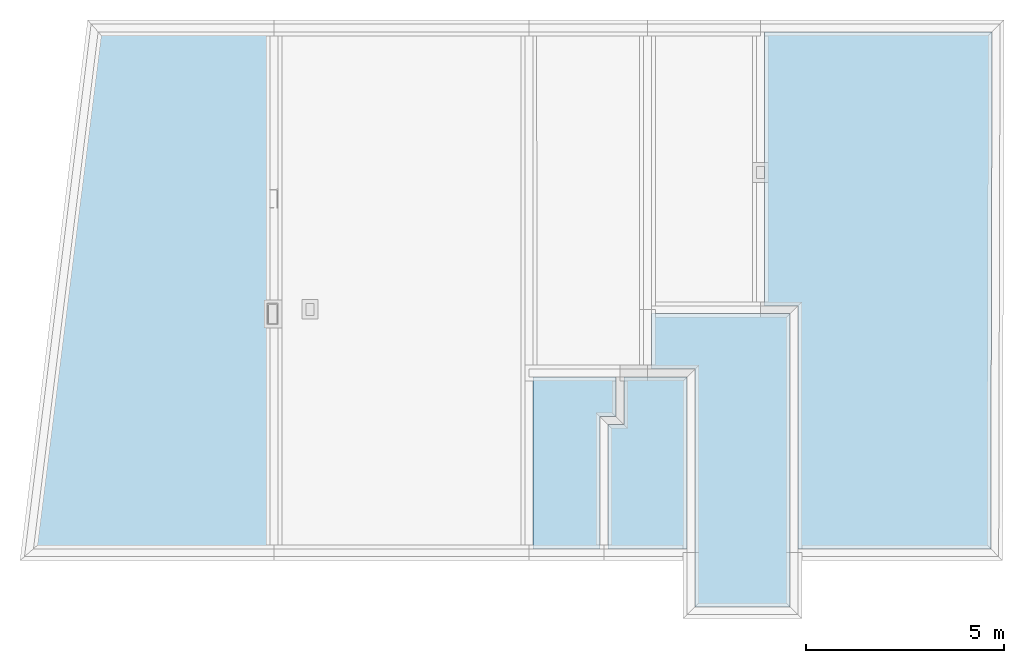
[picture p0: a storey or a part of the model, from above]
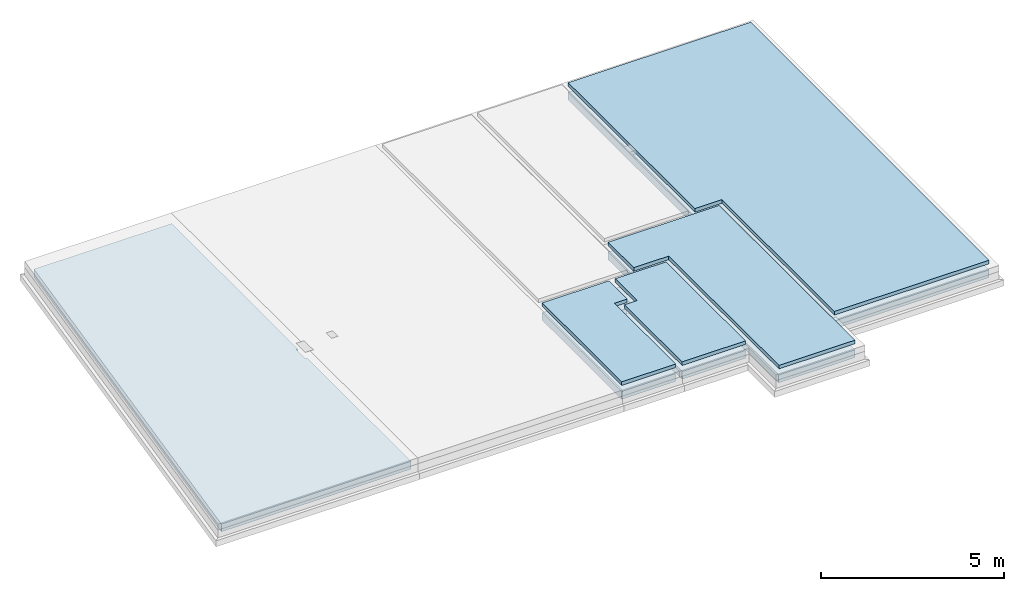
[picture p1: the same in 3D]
Properties of the parts of a building model (IFC2X3)

# File
Description: ISANGARD maison de santé et 9 logements, ViewDefinition [CoordinationView]
File name: G:\2024 Freyssinet\2024_Administratif\Administratif\Eduscol\2024 2025\ATTIC+ ISANGARD\Ressources\Divers\Projte ISANGARD_Ouvrages GO.IFC
Time: 2025-04-09T10:46:59
Author: Philippe PETIT
Organization: Lycée FREYSSINET
Written by: 2023-B
Made in: ATTIC+ Classic-Pack / Graphic-Pack Export_IFC 2023-B
Authorization: Personnes autorisées

# IfcProject, ISANGARD maison de santé et 9 logements
Description: ISANGARD maison de santé et 9 logements; Phase: EXE GROS OEUVRE ISANGARD

# IfcSite
RefLatitude: 0, 0, 0; RefLongitude: 0, 0, 0; RefElevation: 0 m

# IfcBuilding, Classeur ENS Ensemble
LongName: Classeur ENS Ensemble

# IfcBuildingStorey (5)
In: Classeur ENS Ensemble
Name | Description = LongName | Elevation (m)
000 Fondations | 000 Fondations | 0
001 RdC | 001 RdC | 0
002 R+1 | 002 R+1 | 3.3
003 R+2 | 003 R+2 | 6.03
004 Toiture Terrasse | 004 Toiture Terrasse | 8.73

# IfcBeam (184)
Type - PredefinedType: BEAM
Material: Default material
Name | In | Description | NominalLength (m) | CrossSectionArea (m2) | TotalSurfaceArea (m2) | OuterSurfaceArea (m2) | GrossVolume (m3)
3 x poutre fictive -32 | 000 Fondations | poutre fictive -32 | 0.15 | 0 | 0 | 0 | 0
7 x poutre fictive -32 | 000 Fondations | poutre fictive -32 | 0.1 | 0 | 0 | 0 | 0
poutre fictive -32 | 000 Fondations | poutre fictive -32 | 0.45 | 0 | 0 | 0 | 0
2 x poutre fictive -32 | 000 Fondations | poutre fictive -32 | 0.5 | 0 | 0 | 0 | 0
poutre fictive -32 | 000 Fondations | poutre fictive -32 | 0.0198567 | 0 | 0 | 0 | 0
poutre BA | 001 RdC | poutre BA | 4.87555 | 0.08 | 5.93066 | 1.95022 | 0.390044
poutre BA | 001 RdC | poutre BA | 0.0198567 | 0.175 | 0.212728 | 0.0138997 | 0.00347491
poutre BA | 001 RdC | poutre BA | 2.31 | 0.175 | 4.494 | 1.617 | 0.40425
poutre BA | 001 RdC | poutre BA | 1.31 | 0.175 | 2.5765 | 0.917 | 0.22925
poutre BA | 001 RdC | poutre BA | 1.60246 | 0.175 | 3.14951 | 1.12172 | 0.28043
poutre BA | 001 RdC | poutre BA | 1.07043 | 0.125 | 1.73064 | 0.535213 | 0.133803
poutre BA | 001 RdC | poutre BA | 3.215 | 0.07 | 3.6065 | 1.12525 | 0.22505
poutre BA | 001 RdC | poutre BA | 3.405 | 0.07 | 3.8155 | 1.19175 | 0.23835
poutre fictive | 001 RdC | poutre fictive | 0.075 | 0 | 0 | 0 | 0
poutre fictive | 001 RdC | poutre fictive | 0.125 | 0 | 0 | 0 | 0
poutre BA | 001 RdC | poutre BA | 1.23514 | 0.175 | 2.43427 | 0.8646 | 0.21615
poutre fictive | 001 RdC | poutre fictive | 0.63277 | 0 | 0 | 0 | 0
poutre fictive | 001 RdC | poutre fictive | 1.4652 | 0 | 0 | 0 | 0
poutre fictive | 001 RdC | poutre fictive | 5.06775 | 0 | 0 | 0 | 0
poutre fictive | 001 RdC | poutre fictive | 1.465 | 0 | 0 | 0 | 0
poutre fictive | 001 RdC | poutre fictive | 5.07148 | 0 | 0 | 0 | 0
poutre fictive | 001 RdC | poutre fictive | 0.1 | 0 | 0 | 0 | 0
poutre BA | 001 RdC | poutre BA | 0.1 | 0.04 | 0.12 | 0.02 | 0.004
poutre fictive | 001 RdC | poutre fictive | 0.124967 | 0 | 0 | 0 | 0
poutre fictive 285 | 001 RdC | poutre fictive 285 | 0.00999995 | 0 | 0 | 0 | 0
2 x poutre fictive 285 | 001 RdC | poutre fictive 285 | 0.12 | 0 | 0 | 0 | 0
Poutre auto | 001 RdC | Poutre auto | 5.88381 | 0 | 2.35352 | 1.17676 | 0
poutre BA | 001 RdC | poutre BA | 3.665 | 0.125 | 5.6225 | 1.8325 | 0.458125
poutre BA | 001 RdC | poutre BA | 0.120949 | 0.125 | 0.256424 | 0.0604747 | 0.0151187
poutre BA | 001 RdC | poutre BA | 1.56247 | 0.09 | 2.12121 | 0.70311 | 0.140622
poutre BA | 001 RdC | poutre BA | 0.1 | 0.09 | 0.22 | 0.045 | 0.009
poutre fictive 285 | 001 RdC | poutre fictive 285 | 0.1 | 0 | 0 | 0 | 0
poutre BA | 001 RdC | poutre BA | 0.1 | 0.125 | 0.225 | 0.05 | 0.0125
poutre BA | 001 RdC | poutre BA | 2.74002 | 0.09 | 3.65202 | 1.23301 | 0.246601
poutre BA | 001 RdC | poutre BA | 0.249984 | 0.09 | 0.190008 | 0.00000737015 | 0.00000147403
poutre BA | 001 RdC | poutre BA | 1.6 | 0.04 | 1.32 | 0.32 | 0.064
poutre fictive 310 | 001 RdC | poutre fictive 310 | 2.83619 | 0 | 0 | 0 | 0
poutre BA | 001 RdC | poutre BA | 1.2 | 0.04 | 1 | 0.24 | 0.048
poutre fictive 310 | 001 RdC | poutre fictive 310 | 4.34 | 0 | 0 | 0 | 0
Bande noyée 20 x 20 | 001 RdC | Bande noyée 20 x 20 | 1.113 | 0.04 | 0.930403 | 0.222601 | 0.0445201
poutre BA | 001 RdC | poutre BA | 3.93 | 0.175 | 7.572 | 2.751 | 0.68775
poutre BA | 001 RdC | poutre BA | 3.93001 | 0.175 | 7.57217 | 2.751 | 0.687751
poutre BA rive balcon | 001 RdC | poutre BA rive balcon | 1.40084 | 0.075 | 1.8961 | 0.700422 | 0.105063
poutre BA rive balcon | 001 RdC | poutre BA rive balcon | 0.0755851 | 0.075 | 0.182647 | 0.0377926 | 0.00566888
poutre BA rive balcon | 001 RdC | poutre BA rive balcon | 2.63125 | 0.075 | 3.49563 | 1.31563 | 0.197344
poutre BA rive balcon | 001 RdC | poutre BA rive balcon | 4.46986 | 0.075 | 5.88582 | 2.23493 | 0.335239
poutre fictive 290 | 001 RdC | poutre fictive 290 | 1.415 | 0 | 0 | 0 | 0
poutre fictive 290 | 001 RdC | poutre fictive 290 | 0.075 | 0 | 0 | 0 | 0
poutre fictive 290 | 001 RdC | poutre fictive 290 | 1.49 | 0 | 0 | 0 | 0
2 x poutre fictive 306 | 001 RdC | poutre fictive 306 | 0.075 | 0 | 0 | 0 | 0
3 x poutre fictive 306 | 001 RdC | poutre fictive 306 | 0.0755851 | 0 | 0 | 0 | 0
poutre fictive 306 | 001 RdC | poutre fictive 306 | 0.1 | 0 | 0 | 0 | 0
poutre BA rive balcon | 001 RdC | poutre BA rive balcon | 2.36401 | 0.075 | 3.14821 | 1.182 | 0.177301
poutre fictive 306 | 001 RdC | poutre fictive 306 | 4.82129 | 0 | 0 | 0 | 0
poutre fictive 306 | 001 RdC | poutre fictive 306 | 4.98587 | 0 | 0 | 0 | 0
poutre fictive 306 | 001 RdC | poutre fictive 306 | 1.315 | 0 | 0 | 0 | 0
poutre fictive 306 | 001 RdC | poutre fictive 306 | 1.32526 | 0 | 0 | 0 | 0
4 x poutre fictive 305 | 001 RdC | poutre fictive 305 | 0.1 | 0 | 0 | 0 | 0
2 x poutre fictive 305 | 001 RdC | poutre fictive 305 | 1.265 | 0 | 0 | 0 | 0
2 x poutre fictive 305 | 001 RdC | poutre fictive 305 | 0.2 | 0 | 0 | 0 | 0
poutre fictive 305 | 001 RdC | poutre fictive 305 | 0.360863 | 0 | 0 | 0 | 0
2 x poutre fictive 305 | 001 RdC | poutre fictive 305 | 6.74 | 0 | 0 | 0 | 0
poutre BA 20 x 40 | 001 RdC | poutre BA 20 x 40 | 0.2 | 0.08 | 0.32 | 5.92039e-10 | 1.18408e-10
poutre BA 20 x 40 | 001 RdC | poutre BA 20 x 40 | 2.4 | 0.08 | 3.12 | 0.96 | 0.192
poutre fictive 290 | 001 RdC | poutre fictive 290 | 0.2 | 0 | 0 | 0 | 0
poutre BA rive balcon | 001 RdC | poutre BA rive balcon | 2.725 | 0.045 | 2.4975 | 0.8175 | 0.122625
poutre BA rive balcon | 001 RdC | poutre BA rive balcon | 1.49 | 0.045 | 1.386 | 0.447 | 0.06705
poutre voile BA 20 cm | 002 R+1 | poutre voile BA 20 cm | 0.0566479 | 0.596 | 0.956281 | 0.168811 | 0.0337622
poutre voile BA 20 cm | 002 R+1 | poutre voile BA 20 cm | 1.58 | 0.596 | 10.0488 | 4.7084 | 0.94168
poutre voile BA 20 cm | 002 R+1 | poutre voile BA 20 cm | 1.265 | 0.596 | 9.8334 | 3.7697 | 0.75394
poutre voile BA 20 cm | 002 R+1 | poutre voile BA 20 cm | 5.78 | 0.596 | 38.2508 | 17.2244 | 3.44488
2 x poutre voile BA 20 cm | 002 R+1 | poutre voile BA 20 cm | 1.265 | 0.586 | 8.5049 | 3.70645 | 0.74129
poutre fictive 250 | 002 R+1 | poutre fictive 250 | 2.96294 | 0 | 0 | 0 | 0
poutre voile BA 20 cm | 002 R+1 | poutre voile BA 20 cm | 1.56331 | 0.596 | 10.5386 | 4.65865 | 0.931731
poutre voile BA 20 cm | 002 R+1 | poutre voile BA 20 cm | 2.58416 | 0.596 | 16.6588 | 7.70079 | 1.54016
poutre BA 20 x 48 | 002 R+1 | poutre BA 20 x 48 | 2.75374 | 0.096 | 3.84108 | 1.32179 | 0.264359
poutre BA 20 x 35 | 002 R+1 | poutre BA 20 x 35 | 4.57052 | 0.07 | 5.09757 | 1.59968 | 0.319936
poutre BA 20 x 35 | 002 R+1 | poutre BA 20 x 35 | 7.09 | 0.07 | 7.869 | 2.4815 | 0.4963
poutre BA 20 x 35 | 002 R+1 | poutre BA 20 x 35 | 0.2 | 0.07 | 0.29 | 0.07 | 0.014
2 x poutre fictive 250 | 002 R+1 | poutre fictive 250 | 1.5 | 0 | 0 | 0 | 0
2 x poutre fictive 250 | 002 R+1 | poutre fictive 250 | 1.70004 | 0 | 0 | 0 | 0
poutre BA 20 x 35 | 002 R+1 | poutre BA 20 x 35 | 3.62678 | 0.07 | 4.05946 | 1.26937 | 0.253875
poutre fictive 250 | 002 R+1 | poutre fictive 250 | 5.44 | 0 | 0 | 0 | 0
poutre fictive 250 | 002 R+1 | poutre fictive 250 | 3.94 | 0 | 0 | 0 | 0
poutre fictive 250 | 002 R+1 | poutre fictive 250 | 1.6 | 0 | 0 | 0 | 0
poutre fictive 250 | 002 R+1 | poutre fictive 250 | 4.78032 | 0 | 0 | 0 | 0
poutre fictive 250 | 002 R+1 | poutre fictive 250 | 2.86496 | 0 | 0 | 0 | 0
poutre fictive 250 | 002 R+1 | poutre fictive 250 | 2.84982 | 0 | 0 | 0 | 0
poutre BA 25 x 45 | 002 R+1 | poutre BA 25 x 45 | 1.87996 | 0.1125 | 2.74444 | 0.84598 | 0.211495
poutre fictive 250 | 002 R+1 | poutre fictive 250 | 2.00327 | 0 | 0 | 0 | 0
poutre BA 25 x 45 | 002 R+1 | poutre BA 25 x 45 | 0.2 | 0.1125 | 0.3925 | 0.09 | 0.0225
poutre BA 25 x 45 | 002 R+1 | poutre BA 25 x 45 | 3.42999 | 0.1125 | 4.91449 | 1.5435 | 0.385874
poutre BA 25 x 50 | 002 R+1 | poutre BA 25 x 50 | 1.05309 | 0.125 | 1.70464 | 0.526545 | 0.131636
poutre fictive 250 | 002 R+1 | poutre fictive 250 | 2.05496 | 0 | 0 | 0 | 0
poutre BA 25 x 50 | 002 R+1 | poutre BA 25 x 50 | 3.92014 | 0.07 | 4.38216 | 1.37205 | 0.27441
BN 23 | 002 R+1 | BN 23 | 1.73706 | 0.046 | 1.53987 | 0.399525 | 0.0799049
poutre fictive 250 | 002 R+1 | poutre fictive 250 | 2.5404 | 0 | 0 | 0 | 0
poutre fictive 250 | 002 R+1 | poutre fictive 250 | 2.25496 | 0 | 0 | 0 | 0
2 x poutre fictive 250 | 002 R+1 | poutre fictive 250 | 0.324552 | 0 | 0 | 0 | 0
poutre fictive 250 | 002 R+1 | poutre fictive 250 | 0.239541 | 0 | 0 | 0 | 0
poutre BA 25 x 45 | 002 R+1 | poutre BA 25 x 45 | 1.21004 | 0.1125 | 1.80656 | 0.544519 | 0.13613
poutre fictive 250 | 002 R+1 | poutre fictive 250 | 2.20308 | 0 | 0 | 0 | 0
poutre fictive 250 | 002 R+1 | poutre fictive 250 | 2.61028 | 0 | 0 | 0 | 0
BN 23 | 002 R+1 | BN 23 | 1.24257 | 0.046 | 1.11461 | 0.285792 | 0.0571584
poutre BA 25 x 50 | 002 R+1 | poutre BA 25 x 50 | 0.199977 | 0.125 | 0.424965 | 0.0999883 | 0.0249971
poutre BA 25 x 50 | 002 R+1 | poutre BA 25 x 50 | 3.6341 | 0.125 | 5.57615 | 1.81705 | 0.454262
poutre voile BA 20 cm | 002 R+1 | poutre voile BA 20 cm | 0.260305 | 0.596 | 2.25154 | 0.77571 | 0.155142
Poutre auto | 002 R+1 | Poutre auto | 5.3 | 0 | 2.438 | 1.219 | 0
BN 23 | 002 R+1 | BN 23 | 1.55743 | 0.046 | 1.38539 | 0.358208 | 0.0716416
poutre fictive 250 | 002 R+1 | poutre fictive 250 | 1.50225 | 0 | 0 | 0 | 0
poutre voile BA 20 cm | 002 R+1 | poutre voile BA 20 cm | 0.0437805 | 0.596 | 0.874444 | 0.130466 | 0.0260932
BN 23 | 002 R+1 | BN 23 | 1.30238 | 0.046 | 1.16605 | 0.299547 | 0.0599095
poutre voile BA 20 cm | 002 R+1 | poutre voile BA 20 cm | 0.26 | 0.596 | 1.9516 | 0.7748 | 0.15496
poutre BA 25 x 50 | 002 R+1 | poutre BA 25 x 50 | 4.17955 | 0.125 | 6.39432 | 2.08977 | 0.522443
poutre voile BA 20 cm | 002 R+1 | poutre voile BA 20 cm | 2.11262 | 0.596 | 13.6598 | 6.29561 | 1.25912
poutre fictive 250 | 002 R+1 | poutre fictive 250 | 0.0750014 | 0 | 0 | 0 | 0
poutre BA 25 x 50 | 002 R+1 | poutre BA 25 x 50 | 3.74 | 0.125 | 5.735 | 1.87 | 0.4675
PV BA 20 cm | 003 R+2 | PV BA 20 cm | 5.01991 | 0.586 | 32.0107 | 14.7083 | 2.94167
PV BA 20 cm | 003 R+2 | PV BA 20 cm | 0.300186 | 0.586 | 2.46517 | 0.879546 | 0.175909
PV BA 20 cm | 003 R+2 | PV BA 20 cm | 0.2 | 0.586 | 0.666 | 4.36599e-09 | 8.73199e-10
2 x PV BA 20 cm | 003 R+2 | PV BA 20 cm | 0.14 | 0.586 | 1.4624 | 0.4102 | 0.08204
PV BA 20 cm | 003 R+2 | PV BA 20 cm | 4.95291 | 0.586 | 31.5912 | 14.512 | 2.9024
PV BA 20 cm | 003 R+2 | PV BA 20 cm | 0.1 | 0.586 | 1.212 | 0.293 | 0.0586
poutre BA 20 x 45 | 003 R+2 | poutre BA 20 x 45 | 4.84004 | 0.09 | 6.38206 | 2.17802 | 0.435604
poutre BA 20 x 35 | 003 R+2 | poutre BA 20 x 35 | 3.91107 | 0.07 | 4.37217 | 1.36887 | 0.273775
BN 20 | 003 R+2 | BN 20 | 0.0310394 | 0.04 | 0.117875 | 0.00620788 | 0.00124158
BN 20 | 003 R+2 | BN 20 | 1.70036 | 0.04 | 1.39418 | 0.340072 | 0.0680145
BN 20 | 003 R+2 | BN 20 | 1.28 | 0.04 | 1.064 | 0.256 | 0.0512
BN 20 | 003 R+2 | BN 20 | 1.22 | 0.04 | 1.016 | 0.244 | 0.0488
poutre BA 20 x 40 | 003 R+2 | poutre BA 20 x 40 | 4.44 | 0.08 | 5.408 | 1.776 | 0.3552
2 x poutre BA 20 x 30 | 003 R+2 | poutre BA 20 x 30 | 3.44 | 0.06 | 3.5 | 1.032 | 0.2064
PV BA 20 cm | 003 R+2 | PV BA 20 cm | 0.0114892 | 0.586 | 0.883596 | 0.0336634 | 0.00673267
2 x poutre BA 20 x 30 | 003 R+2 | poutre BA 20 x 30 | 0.1 | 0.06 | 0.13 | 0.03 | 0.006
poutre BA 20 x 50 | 003 R+2 | poutre BA 20 x 50 | 2.76138 | 0.1 | 3.96593 | 1.38069 | 0.276138
PV BA 20 cm | 003 R+2 | PV BA 20 cm | 0.0885108 | 0.586 | 0.914404 | 0.259337 | 0.0518673
PV BA 20 cm | 003 R+2 | PV BA 20 cm | 1.65004 | 0.586 | 10.9153 | 4.83462 | 0.966925
3 x Poutre auto | 003 R+2 | Poutre auto | 1.2 | 0 | 0.48 | 0.24 | 0
Poutre auto | 003 R+2 | Poutre auto | 0.151589 | 0 | 0.0606357 | 0.0303178 | 0
4 x poutre fictive 250 | 003 R+2 | poutre fictive 250 | 0.1 | 0 | 0 | 0 | 0
PV BA 20 cm | 003 R+2 | PV BA 20 cm | 2.725 | 0.64 | 19.17 | 8.72 | 1.744
PV BA 20 cm | 003 R+2 | PV BA 20 cm | 2.775 | 0.64 | 19.51 | 8.88 | 1.776
2 x poutre fictive 250 | 003 R+2 | poutre fictive 250 | 0.14 | 0 | 0 | 0 | 0
2 x poutre fictive 250 | 003 R+2 | poutre fictive 250 | 0.0114892 | 0 | 0 | 0 | 0
2 x poutre fictive 250 | 003 R+2 | poutre fictive 250 | 2.81351 | 0 | 0 | 0 | 0
2 x poutre fictive 250 | 003 R+2 | poutre fictive 250 | 6.88 | 0 | 0 | 0 | 0
PV BA 20 cm | 003 R+2 | PV BA 20 cm | 3.84 | 0.586 | 24.6244 | 11.2512 | 2.25024
PV BA 20 cm | 003 R+2 | PV BA 20 cm | 0.138512 | 0.586 | 1.00172 | 0.18016 | 0.036032
Poutre auto | 003 R+2 | Poutre auto | 1.04841 | 0 | 0.419364 | 0.209682 | 0
poutre BA 20 x 30 | 003 R+2 | poutre BA 20 x 30 | 0.2 | 0.06 | 0.14 | 4.4703e-10 | 8.9406e-11

# IfcColumn (8)
Type - PredefinedType: COLUMN
Description: Poteau BA; Material: Default material
Name | In | GrossVolume (m3) = NetVolume (m3) | TotalSurfaceArea (m2) | CrossSectionArea (m2) | NominalLength (m) | OuterSurfaceArea (m2)
Poteau BA | 001 RdC | 0.39625 | 5.005 | 0.125 | 3.17 | 4.755
Poteau BA | 001 RdC | 0.1902 | 3.29 | 0.06 | 3.17 | 3.17
Poteau BA | 001 RdC | 0.2853 | 4.301 | 0.09 | 3.17 | 4.121
Poteau BA | 001 RdC | 0.183 | 3.17 | 0.06 | 3.05 | 3.05
Poteau BA | 002 R+1 | 0.125 | 2.35 | 0.05 | 2.5 | 2.25
Poteau BA | 002 R+1 | 0.1 | 2.08 | 0.04 | 2.5 | 2
2 x Poteau BA | 003 R+2 | 0.1 | 2.08 | 0.04 | 2.5 | 2

# IfcDoor (18)
Description: Porte
Name | In | OverallHeight (m) | OverallWidth (m)
4 x BL 100 x 215 | 001 RdC | 2.15 | 1
PE 93 x 212 | 001 RdC | 2.15 | 1
2 x PS 103 x 210 | 001 RdC | 2.1 | 1.03
PE 95 x 215 | 001 RdC | 2.15 | 0.95
2 x BL 170 x 215 | 001 RdC | 2.15 | 1.7
4 x PE 93 x 215 | 002 R+1 | 2.15 | 1
4 x PE 93 x 215 | 003 R+2 | 2.15 | 1

# IfcFooting (34)
In: 000 Fondations
Description: Semelle filante 40x20; Material: Default material
Name | PredefinedType
31 x Semelle filante 40x20 | STRIP_FOOTING
3 x Semelle filante 40x20 | PAD_FOOTING

# IfcOpeningElement (66)
Name | In | Description | NominalArea (m2)
5 x BL 300 x 115 | 001 RdC | BL 300 x 115 | 3.45
BL 200 x 115 | 001 RdC | BL 200 x 115 | 2.3
4 x BL 100 x 215 | 001 RdC | BL 100 x 215 | 2.15
PE 93 x 212 | 001 RdC | PE 93 x 212 | 2.15
4 x BL 90 x 115 | 001 RdC | BL 90 x 115 | 1.035
BL 90 x 195 | 001 RdC | BL 90 x 195 | 1.755
BL 300 x 215 | 001 RdC | BL 300 x 215 | 6.45
2 x PS 103 x 210 | 001 RdC | PS 103 x 210 | 2.163
PE 95 x 215 | 001 RdC | PE 95 x 215 | 2.0425
2 x BL 170 x 215 | 001 RdC | BL 170 x 215 | 3.655
10 x BL 90 x 165 | 002 R+1 | BL 90 x 165 | 1.485
3 x BL 300 x 215 | 002 R+1 | BL 300 x 215 | 6.45
4 x PE 93 x 215 | 002 R+1 | PE 93 x 215 | 2.15
BL 80 x 165 | 002 R+1 | BL 80 x 165 | 1.32
BL 200 x 215 | 002 R+1 | BL 200 x 215 | 4.3
BL 90 x 115 | 002 R+1 | BL 90 x 115 | 1.035
BL 100 x 215 | 002 R+1 | BL 100 x 215 | 2.15
12 x BL 90 x 165 | 003 R+2 | BL 90 x 165 | 1.485
BL 300 x 215 | 003 R+2 | BL 300 x 215 | 6
2 x BL 200 x 200 | 003 R+2 | BL 200 x 200 | 4
BL 100 x 200 | 003 R+2 | BL 100 x 200 | 2
BL 80 x 165 | 003 R+2 | BL 80 x 165 | 1.32
BL 200 x 215 | 003 R+2 | BL 200 x 215 | 4.3
4 x PE 93 x 215 | 003 R+2 | PE 93 x 215 | 2.15
BL 90 x 115 | 003 R+2 | BL 90 x 115 | 1.035

# IfcSlab (73)
Description: description dalle à préciser; PredefinedType: FLOOR; Material: Default material
Pset_SlabCommon - LoadBearing: yes
Name | In | GrossVolume (m3) = NetVolume (m3) | Perimeter (m) | GrossArea (m2) = NetArea (m2) | NominalWidth (m)
dallage porté 20 cm | 000 Fondations | 1.9896 | 13.88 | 9.948 | 0.2
dallage porté 20 cm | 000 Fondations | 4.11542 | 20.1401 | 20.5771 | 0.2
dallage porté 20 cm | 000 Fondations | 15.1952 | 38.9973 | 75.976 | 0.2
dallage porté 20 cm | 000 Fondations | 4.49197 | 23.0099 | 22.4599 | 0.2
dallage porté 20 cm | 000 Fondations | 7.03557 | 32.9179 | 35.1779 | 0.2
dallage porté 20 cm | 000 Fondations | 17.3393 | 39.8021 | 86.6966 | 0.2
dallage porté 20 cm | 000 Fondations | 14.6988 | 37.9453 | 73.4938 | 0.2
chape sur isolant 12 cm | 000 Fondations | 2.86188 | 22.635 | 23.849 | 0.12
chape sur isolant 12 cm | 000 Fondations | 2.20056 | 19.14 | 18.338 | 0.12
chape sur isolant 12 cm | 000 Fondations | 8.3669 | 37.5968 | 69.7242 | 0.12
chape sur isolant 12 cm | 000 Fondations | 2.31383 | 21.7999 | 19.2819 | 0.12
chape sur isolant 12 cm | 000 Fondations | 0.93336 | 12.88 | 7.778 | 0.12
chape sur isolant 12 cm | 000 Fondations | 0.984 | 12.68 | 8.2 | 0.12
hérisson 26 cm | 000 Fondations | 17.51 | 36.6391 | 67.3463 | 0.26
hérisson 26 cm | 000 Fondations | 21.1921 | 38.6021 | 81.5081 | 0.26
hérisson 26 cm | 000 Fondations | 6.1786 | 22.615 | 23.7639 | 0.26
hérisson 26 cm | 000 Fondations | 4.76783 | 19.14 | 18.3378 | 0.26
hérisson 26 cm | 000 Fondations | 18.1283 | 37.5968 | 69.7242 | 0.26
hérisson 26 cm | 000 Fondations | 2.02228 | 12.88 | 7.778 | 0.26
hérisson 26 cm | 000 Fondations | 2.132 | 12.68 | 8.2 | 0.26
hérisson 26 cm | 000 Fondations | 5.02111 | 21.8099 | 19.3119 | 0.26
Dalle BA 20 cm | 001 RdC | 1.4855 | 13.0694 | 7.42749 | 0.2
Dalle BA 25 cm | 001 RdC | 3.7208 | 20.48 | 18.604 | 0.2
Dalle BA 25 cm | 001 RdC | 1.9016 | 13.48 | 9.508 | 0.2
Dalle BA 25 cm | 001 RdC | 15.1072 | 34.9826 | 60.4286 | 0.25
Dalle BA 25 cm | 001 RdC | 22.7054 | 51.7543 | 90.8216 | 0.25
Dalle BA 20 cm | 001 RdC | 0.811065 | 8.56147 | 4.05533 | 0.2
Dalle BA 20 cm | 001 RdC | 1.66055 | 23.4553 | 8.30274 | 0.2
Dalle BA 20 cm | 001 RdC | 17.2387 | 54.7424 | 86.1934 | 0.2
Dalle BA 20 cm | 001 RdC | 1.88282 | 14.9676 | 9.4141 | 0.2
Dalle BA 20 cm | 001 RdC | 1.58827 | 11.2724 | 7.94133 | 0.2
Dalle BA 20 cm | 001 RdC | 1.6396 | 13.28 | 8.198 | 0.2
Dalle BA 25 cm | 001 RdC | 1.37702 | 10.7935 | 5.50808 | 0.25
Dalle BA 20 cm | 001 RdC | 1.33148 | 12.169 | 6.65739 | 0.2
Dalle BA 20 cm | 001 RdC | 1.22516 | 12.4474 | 6.44821 | 0.19
Dalle BA 20 cm | 001 RdC | 1.70522 | 16.01 | 8.5261 | 0.2
isolant sous face 15 | 001 RdC | 1.27892 | 16.01 | 8.5261 | 0.15
Dalle BA 20 cm | 001 RdC | 0.8204 | 8.53 | 4.102 | 0.2
Dalle BA 18 cm | 002 R+1 | 0.630749 | 8.05916 | 3.50416 | 0.18
Dalle BA 23 cm | 002 R+1 | 1.13818 | 10.01 | 4.9486 | 0.23
Dalle BA 23 cm | 002 R+1 | 1.07999 | 9.61 | 4.6956 | 0.23
Dalle BA 18 cm | 002 R+1 | 2.09952 | 17.78 | 11.664 | 0.18
Dalle BA 18 cm | 002 R+1 | 1.23917 | 11.2491 | 6.88426 | 0.18
Dalle BA 18 cm | 002 R+1 | 1.40371 | 12.9581 | 7.79839 | 0.18
Dalle BA 23 cm | 002 R+1 | 1.23721 | 11.6362 | 5.37917 | 0.23
Dalle BA 23 cm | 002 R+1 | 2.52402 | 14.0399 | 10.974 | 0.23
Dalle BA 23 cm | 002 R+1 | 0.932159 | 8.11645 | 4.05287 | 0.23
Dalle BA 23 cm | 002 R+1 | 3.30361 | 15.7797 | 14.3635 | 0.23
Dalle BA 23 cm | 002 R+1 | 1.29778 | 9.65956 | 5.64253 | 0.23
Dalle BA 23 cm | 002 R+1 | 7.61935 | 23.66 | 33.1276 | 0.23
Dalle BA 23 cm | 002 R+1 | 9.00261 | 26.6831 | 39.1418 | 0.23
Dalle BA 23 cm | 002 R+1 | 2.67964 | 18.1 | 11.6506 | 0.23
Dalle BA 23 cm | 002 R+1 | 2.0204 | 13.9149 | 8.78436 | 0.23
Dalle BA 23 cm | 002 R+1 | 4.59393 | 18.96 | 19.9736 | 0.23
Dalle BA 23 cm | 002 R+1 | 8.0811 | 26.1539 | 35.1352 | 0.23
Dalle BA 23 cm | 002 R+1 | 8.4789 | 27.0246 | 36.8648 | 0.23
Dalle BA 23 cm | 002 R+1 | 4.70487 | 18.7817 | 20.456 | 0.23
Dalle BA 23 cm | 002 R+1 | 0.511386 | 5.96462 | 2.22342 | 0.23
Dalle BA 23 cm | 002 R+1 | 4.36871 | 17.7419 | 18.9944 | 0.23
Dalle BA 20 cm | 003 R+2 | 7.14872 | 26.4039 | 35.7436 | 0.2
Dalle BA 20 cm | 003 R+2 | 0.911289 | 9.00256 | 4.55645 | 0.2
Dalle BA 20 cm | 003 R+2 | 10.2801 | 40.9136 | 51.4003 | 0.2
Dalle BA 20 cm | 003 R+2 | 4.1476 | 26.2404 | 20.738 | 0.2
Dalle BA 20 cm | 003 R+2 | 1.14452 | 10.9 | 5.7226 | 0.2
Dalle BA 20 cm | 003 R+2 | 0.42032 | 5.8 | 2.1016 | 0.2
Dalle BA 20 cm | 003 R+2 | 0.263 | 5.16 | 1.315 | 0.2
Dalle BA 20 cm | 003 R+2 | 7.31641 | 23.7727 | 36.582 | 0.2
Dalle BA 20 cm | 003 R+2 | 5.29558 | 20.5861 | 26.4779 | 0.2
Dalle BA 20 cm | 003 R+2 | 2.50712 | 14.8613 | 12.5356 | 0.2
Dalle BA 20 cm | 003 R+2 | 8.08383 | 28.4824 | 40.4191 | 0.2
Dalle BA 20 cm | 003 R+2 | 7.20179 | 24.9446 | 36.009 | 0.2
Dalle BA 20 cm | 003 R+2 | 4.20163 | 19.867 | 21.0082 | 0.2
Étanchéité sur isolant | 004 Toiture Terrasse | 45.08 | 80.535 | 281.75 | 0.16

# IfcWall (175)
Type - PredefinedType: STANDARD
Pset_WallCommon - LoadBearing: yes
Name | In | Description | Material | GrossSideAreaLeft (m2) | GrossSideAreaRight (m2) | NetSideAreaRight (m2) | NominalHeight (m) | NetSideArea (m2) | NetSideAreaLeft (m2) | NetVolume (m3) | NominalLength (m) | NetFootprintArea (m2) | GrossVolume (m3) | GrossFootprintArea (m2) | NominalWidth (m) | GrossSideArea (m2)
voile BA 20 cm | 001 RdC | voile BA 20 cm | voile BA 20 cm 0.2 m | 35.0534 | 34.1768 | 24.1268 | 3.17 | 24.7236 | 25.0034 | 4.94472 | 10.9696 | 1.79392 | 6.95472 | 2.19392 | 0.2 | 34.7736
voile BA 20 cm | 001 RdC | voile BA 20 cm | voile BA 20 cm 0.2 m | 4.50753 | 5.1499 | 5.1499 | 3.22 | 4.82872 | 4.50753 | 0.965743 | 1.4996 | 0.29992 | 0.965743 | 0.29992 | 0.2 | 4.82872
voile BA 20 cm | 001 RdC | voile BA 20 cm | voile BA 20 cm 0.2 m | 3.72525e-09 | 3.72525e-09 | 3.72525e-09 | 2.5 | 3.72525e-09 | 3.72525e-09 | 7.45051e-10 | 0.2 | 0.04 | 7.45051e-10 | 0.04 | 0.2 | 3.72525e-09
voile BA 20 cm | 001 RdC | voile BA 20 cm | voile BA 20 cm 0.2 m | 4.3953 | 4.7173 | 4.7173 | 3.22 | 4.7173 | 4.3953 | 0.94346 | 1.465 | 0.293 | 0.94346 | 0.293 | 0.2 | 4.7173
voile BA 20 cm | 001 RdC | voile BA 20 cm | voile BA 20 cm 0.2 m | 7.728 | 9.016 | 9.016 | 3.22 | 8.372 | 7.728 | 1.6744 | 2.6 | 0.52 | 1.6744 | 0.52 | 0.2 | 8.372
voile BA 20 cm | 001 RdC | voile BA 20 cm | voile BA 20 cm 0.2 m | 5.0393 | 4.3953 | 2.2323 | 3.22 | 2.5543 | 2.8763 | 0.51086 | 1.465 | 0.087 | 0.94346 | 0.293 | 0.2 | 4.7173
voile BA 20 cm | 001 RdC | voile BA 20 cm | voile BA 20 cm 0.2 m | 4.83 | 4.508 | 4.508 | 3.22 | 4.83 | 4.83 | 0.966 | 1.5 | 0.3 | 0.966 | 0.3 | 0.2 | 4.83
voile BA 20 cm | 001 RdC | voile BA 20 cm | voile BA 20 cm 0.2 m | 9.177 | 8.855 | 7.82 | 3.22 | 8.142 | 8.142 | 1.6284 | 2.85 | 0.57 | 1.8354 | 0.57 | 0.2 | 9.177
voile BA 20 cm | 001 RdC | voile BA 20 cm | voile BA 20 cm 0.2 m | 4.8287 | 4.5067 | 4.5067 | 3.22 | 4.8287 | 4.8287 | 0.96574 | 1.4996 | 0.299919 | 0.96574 | 0.299919 | 0.2 | 4.8287
voile BA 20 cm | 001 RdC | voile BA 20 cm | voile BA 20 cm 0.2 m | 8.855 | 8.855 | 8.855 | 3.22 | 8.855 | 8.855 | 1.771 | 2.75 | 0.55 | 1.771 | 0.55 | 0.2 | 8.855
voile BA 20 cm | 001 RdC | voile BA 20 cm | voile BA 20 cm 0.2 m | 3.98052 | 3.65852 | 1.62485 | 3.22 | 1.94685 | 1.94685 | 0.38937 | 1.23619 | 0.0580587 | 0.796105 | 0.247238 | 0.2 | 3.98052
voile BA 20 cm | 001 RdC | voile BA 20 cm | voile BA 20 cm 0.2 m | 3.22 | 3.864 | 3.864 | 3.22 | 3.542 | 3.22 | 0.7084 | 1.1 | 0.22 | 0.7084 | 0.22 | 0.2 | 3.542
voile BA 20 cm | 001 RdC | voile BA 20 cm | voile BA 20 cm 0.2 m | 1.288 | 1.288 | 1.288 | 3.22 | 1.288 | 1.288 | 0.2576 | 0.4 | 0.08 | 0.2576 | 0.08 | 0.2 | 1.288
voile BA 20 cm | 001 RdC | voile BA 20 cm | voile BA 20 cm 0.2 m | 10.1108 | 9.4668 | 9.4668 | 3.22 | 9.7888 | 10.1108 | 1.95776 | 3.04 | 0.608 | 1.95776 | 0.608 | 0.2 | 9.7888
voile BA 20 cm | 001 RdC | voile BA 20 cm | voile BA 20 cm 0.2 m | 13.3308 | 14.2968 | 14.2968 | 3.22 | 13.9748 | 13.3308 | 2.79496 | 4.34 | 0.868 | 2.79496 | 0.868 | 0.2 | 13.9748
2 x voile BA 20 cm | 001 RdC | voile BA 20 cm | voile BA 20 cm 0.2 m | 4.65031e-09 | 4.65031e-09 | 4.65031e-09 | 3.1 | 4.65031e-09 | 4.65031e-09 | 9.30061e-10 | 0.2 | 0.04 | 9.30061e-10 | 0.04 | 0.2 | 4.65031e-09
voile BA 20 cm | 001 RdC | voile BA 20 cm | voile BA 20 cm 0.2 m | 0.317 | 0.634 | 0.634 | 3.17 | 0.634 | 0.317 | 0.1268 | 0.2 | 0.04 | 0.1268 | 0.04 | 0.2 | 0.634
voile BA 20 cm | 001 RdC | voile BA 20 cm | voile BA 20 cm 0.2 m | 4.186 | 3.864 | 3.864 | 3.22 | 4.186 | 4.186 | 0.8372 | 1.3 | 0.26 | 0.8372 | 0.26 | 0.2 | 4.186
voile BA 20 cm | 001 RdC | voile BA 20 cm | voile BA 20 cm 0.2 m | 15.6784 | 16.3967 | 12.4717 | 3.17 | 12.1126 | 11.7534 | 2.42251 | 5.05917 | 0.967648 | 3.20751 | 1.01183 | 0.2 | 16.0376
voile BA 20 cm | 001 RdC | voile BA 20 cm | voile BA 20 cm 0.2 m | 36.9005 | 37.5461 | 37.5461 | 3.22 | 37.2233 | 36.9005 | 7.44466 | 11.56 | 2.31201 | 7.44466 | 2.31201 | 0.2 | 37.2233
voile BA 20 cm | 001 RdC | voile BA 20 cm | voile BA 20 cm 0.2 m | 13.9748 | 14.6188 | 14.6188 | 3.22 | 14.2968 | 13.9748 | 2.85936 | 4.44 | 0.888 | 2.85936 | 0.888 | 0.2 | 14.2968
voile BA 20 cm | 001 RdC | voile BA 20 cm | voile BA 20 cm 0.2 m | 17.8312 | 17.8312 | 17.8312 | 3.17 | 17.8312 | 17.8312 | 3.56625 | 5.625 | 1.125 | 3.56625 | 1.125 | 0.2 | 17.8312
voile BA 20 cm | 001 RdC | voile BA 20 cm | voile BA 20 cm 0.2 m | 3.84003 | 3.84003 | 3.84003 | 3.17 | 3.84003 | 3.84003 | 0.768006 | 1.21137 | 0.242273 | 0.768006 | 0.242273 | 0.2 | 3.84003
voile BA 20 cm | 001 RdC | voile BA 20 cm | voile BA 20 cm 0.2 m | 14.3845 | 13.8249 | 8.4132 | 3.17 | 8.69299 | 8.97279 | 1.7386 | 4.44944 | 0.707401 | 2.82095 | 0.889889 | 0.2 | 14.1047
voile BA 20 cm | 001 RdC | voile BA 20 cm | voile BA 20 cm 0.2 m | 3.059 | 2.415 | 2.415 | 3.22 | 2.737 | 3.059 | 0.5474 | 0.85 | 0.17 | 0.5474 | 0.17 | 0.2 | 2.737
voile BA 20 cm | 001 RdC | voile BA 20 cm | voile BA 20 cm 0.2 m | 19.4994 | 18.8538 | 16.7838 | 3.22 | 17.1066 | 17.4294 | 3.42132 | 5.95547 | 1.19109 | 3.83532 | 1.19109 | 0.2 | 19.1766
voile BA 20 cm | 001 RdC | voile BA 20 cm | voile BA 20 cm 0.2 m | 15.6878 | 16.3302 | 9.88016 | 3.22 | 9.55898 | 9.2378 | 1.9118 | 4.97173 | 0.994347 | 3.2018 | 0.994347 | 0.2 | 16.009
voile BA 20 cm | 001 RdC | voile BA 20 cm | voile BA 20 cm 0.2 m | 0.399973 | 0.399973 | 0.211718 | 3.17 | 0.211718 | 0.211718 | 0.0423436 | 0.126175 | 0.00772279 | 0.0799947 | 0.0252349 | 0.2 | 0.399973
voile BA 20 cm | 001 RdC | voile BA 20 cm | voile BA 20 cm 0.2 m | 8.2007 | 8.2007 | 7.21768 | 2.97 | 7.21768 | 7.21768 | 1.44354 | 2.76118 | 0.552235 | 1.64014 | 0.552235 | 0.2 | 8.2007
voile BA 20 cm | 001 RdC | voile BA 20 cm | voile BA 20 cm 0.2 m | 5.474 | 5.152 | 3.397 | 3.22 | 3.719 | 3.719 | 0.7438 | 1.7 | 0.34 | 1.0948 | 0.34 | 0.2 | 5.474
voile BA 20 cm | 001 RdC | voile BA 20 cm | voile BA 20 cm 0.2 m | 19.1442 | 18.4259 | 14.9759 | 3.17 | 15.335 | 15.6942 | 3.067 | 5.92587 | 1.18517 | 3.757 | 1.18517 | 0.2 | 18.785
voile BA 20 cm | 001 RdC | voile BA 20 cm | voile BA 20 cm 0.2 m | 0.319473 | 0.319473 | 0.267486 | 3.17 | 0.267486 | 0.267486 | 0.0534971 | 0.10078 | 0.020156 | 0.0638946 | 0.020156 | 0.2 | 0.319473
voile BA 20 cm | 001 RdC | voile BA 20 cm | voile BA 20 cm 0.2 m | 0.645301 | 0.645301 | 0.645301 | 3.22 | 0.645301 | 0.645301 | 0.12906 | 0.200404 | 0.0400808 | 0.12906 | 0.0400808 | 0.2 | 0.645301
voile BA 20 cm | 001 RdC | voile BA 20 cm | voile BA 20 cm 0.2 m | 0.645299 | 0.645299 | 0.645299 | 3.22 | 0.645299 | 0.645299 | 0.12906 | 0.200403 | 0.0400807 | 0.12906 | 0.0400807 | 0.2 | 0.645299
voile BA 20 cm | 001 RdC | voile BA 20 cm | voile BA 20 cm 0.2 m | 13.7578 | 13.1238 | 13.1238 | 3.17 | 13.7578 | 13.7578 | 2.75156 | 4.34 | 0.868 | 2.75156 | 0.868 | 0.2 | 13.7578
voile BA 20 cm | 001 RdC | voile BA 20 cm | voile BA 20 cm 0.2 m | 5.15069 | 4.83369 | 4.83369 | 3.17 | 5.15069 | 5.15069 | 1.03014 | 1.62482 | 0.324964 | 1.03014 | 0.324964 | 0.2 | 5.15069
voile BA 20 cm | 001 RdC | voile BA 20 cm | voile BA 20 cm 0.2 m | 6.44 | 6.762 | 4.599 | 3.22 | 4.599 | 4.277 | 0.9198 | 2.1 | 0.214 | 1.3524 | 0.42 | 0.2 | 6.762
voile BA 20 cm | 001 RdC | voile BA 20 cm | voile BA 20 cm 0.2 m | 0.503435 | 0.503435 | 0.503435 | 3.17 | 0.503435 | 0.503435 | 0.100687 | 0.158812 | 0.0317625 | 0.100687 | 0.0317625 | 0.2 | 0.503435
voile BA 20 cm | 001 RdC | voile BA 20 cm | voile BA 20 cm 0.2 m | 18.6239 | 18.6239 | 18.615 | 3.22 | 18.615 | 18.615 | 3.72301 | 5.78381 | 1.15594 | 3.72478 | 1.15676 | 0.2 | 18.6239
voile BA 20 cm | 001 RdC | voile BA 20 cm | voile BA 20 cm 0.2 m | 3.542 | 3.22 | 3.22 | 3.22 | 3.542 | 3.542 | 0.7084 | 1.1 | 0.22 | 0.7084 | 0.22 | 0.2 | 3.542
voile BA 20 cm | 001 RdC | voile BA 20 cm | voile BA 20 cm 0.2 m | 1.932 | 1.932 | 1.932 | 3.22 | 2.254 | 1.932 | 0.4508 | 0.7 | 0.14 | 0.4508 | 0.14 | 0.2 | 2.254
voile BA 20 cm | 001 RdC | voile BA 20 cm | voile BA 20 cm 0.2 m | 7.084 | 6.762 | 3.10944 | 3.22 | 3.43144 | 3.43144 | 0.686287 | 2.2 | 0.100227 | 1.4168 | 0.44 | 0.2 | 7.084
voile BA 20 cm | 001 RdC | voile BA 20 cm | voile BA 20 cm 0.2 m | 5.474 | 5.796 | 2.14666 | 3.22 | 2.14666 | 1.82466 | 0.429332 | 1.8 | 0.0205266 | 1.1592 | 0.36 | 0.2 | 5.796
voile BA 20 cm | 001 RdC | voile BA 20 cm | voile BA 20 cm 0.2 m | 1.16999 | 1.80399 | 1.80399 | 3.17 | 1.48699 | 1.16999 | 0.297398 | 0.469082 | 0.0938163 | 0.297398 | 0.0938163 | 0.2 | 1.48699
voile BA 20 cm | 001 RdC | voile BA 20 cm | voile BA 20 cm 0.2 m | 4.76591e-09 | 4.76591e-09 | 4.76591e-09 | 3.22 | 4.76591e-09 | 4.76591e-09 | 9.53183e-10 | 0.2 | 0.04 | 9.53183e-10 | 0.04 | 0.2 | 4.76591e-09
voile BA 20 cm | 001 RdC | voile BA 20 cm | voile BA 20 cm 0.2 m | 1.48871 | 1.48871 | 0.479017 | 3.17 | 0.479017 | 0.479017 | 0.0958034 | 0.469625 | 0 | 0.297742 | 0.0939249 | 0.2 | 1.48871
voile BA 20 cm | 001 RdC | voile BA 20 cm | voile BA 20 cm 0.2 m | 19.8771 | 19.8771 | 14.3852 | 3.17 | 14.3852 | 14.3852 | 2.87705 | 6.27038 | 1.06414 | 3.97542 | 1.25408 | 0.2 | 19.8771
voile BA 20 cm | 001 RdC | voile BA 20 cm | voile BA 20 cm 0.2 m | 1.14411 | 1.14411 | 0.370638 | 3.17 | 0.370638 | 0.370638 | 0.0741276 | 0.360918 | 0.00023269 | 0.228822 | 0.0721837 | 0.2 | 1.14411
voile BA 20 cm | 001 RdC | voile BA 20 cm | voile BA 20 cm 0.2 m | 0.322 | 0.644 | 0.644 | 3.22 | 0.644 | 0.322 | 0.1288 | 0.2 | 0.04 | 0.1288 | 0.04 | 0.2 | 0.644
mur BBM 20 cm | 002 R+1 | mur BBM 20 cm | mur BBM 20 cm 0.2 m | 11.5446 | 11.1033 | 8.13331 | 2.5 | 8.35397 | 8.57463 | 1.67079 | 4.52959 | 0.905918 | 2.26479 | 0.905918 | 0.2 | 11.324
mur BBM 20 cm | 002 R+1 | mur BBM 20 cm | mur BBM 20 cm 0.2 m | 7.12453 | 6.87453 | 5.38953 | 2.5 | 5.63953 | 5.63953 | 1.12791 | 2.84981 | 0.569962 | 1.42491 | 0.569962 | 0.2 | 7.12453
mur BBM 20 cm | 002 R+1 | mur BBM 20 cm | mur BBM 20 cm 0.2 m | 3.5 | 3.75 | 3.75 | 2.5 | 3.75 | 3.5 | 0.75 | 1.5 | 0.3 | 0.75 | 0.3 | 0.2 | 3.75
voile BA 20 cm | 002 R+1 | voile BA 20 cm | voile BA 20 cm 0.2 m | 2.84047 | 2.84047 | 0.690469 | 2.5 | 0.690469 | 0.690469 | 0.138094 | 1.13619 | 0.0272375 | 0.568094 | 0.227238 | 0.2 | 2.84047
mur BBM 20 cm | 002 R+1 | mur BBM 20 cm | mur BBM 20 cm 0.2 m | 5.5 | 5.5 | 2.48454 | 2.5 | 2.48454 | 2.48454 | 0.496908 | 2.2 | 0.44 | 1.1 | 0.44 | 0.2 | 5.5
mur BBM 20 cm | 002 R+1 | mur BBM 20 cm | mur BBM 20 cm 0.2 m | 3.25 | 3 | 3 | 2.5 | 3.25 | 3.25 | 0.65 | 1.3 | 0.26 | 0.65 | 0.26 | 0.2 | 3.25
mur BBM 20 cm | 002 R+1 | mur BBM 20 cm | mur BBM 20 cm 0.2 m | 11.8647 | 12.0532 | 5.60323 | 2.5 | 5.69792 | 5.41468 | 1.13958 | 4.85917 | 0.971834 | 2.42958 | 0.971834 | 0.2 | 12.1479
mur BBM 20 cm | 002 R+1 | mur BBM 20 cm | mur BBM 20 cm 0.2 m | 4.00076 | 4.49949 | 4.49949 | 2.5 | 4.25012 | 4.00076 | 0.850024 | 1.70005 | 0.34001 | 0.850024 | 0.34001 | 0.2 | 4.25012
voile BA 20 cm | 002 R+1 | voile BA 20 cm | voile BA 20 cm 0.2 m | 10.9125 | 10.9125 | 10.9125 | 2.5 | 10.9125 | 10.9125 | 2.1825 | 4.365 | 0.873 | 2.1825 | 0.873 | 0.2 | 10.9125
mur BBM 20 cm | 002 R+1 | mur BBM 20 cm | mur BBM 20 cm 0.2 m | 15.1393 | 14.638 | 11.668 | 2.5 | 11.9187 | 12.1693 | 2.38374 | 5.95547 | 1.19109 | 2.97774 | 1.19109 | 0.2 | 14.8887
mur BBM 20 cm | 002 R+1 | mur BBM 20 cm | mur BBM 20 cm 0.2 m | 2.63273 | 2.63273 | 2.63273 | 2.5 | 2.88273 | 2.63273 | 0.576545 | 1.15309 | 0.230618 | 0.576545 | 0.230618 | 0.2 | 2.88273
voile BA 20 cm | 002 R+1 | voile BA 20 cm | voile BA 20 cm 0.2 m | 1.25 | 1.75 | 1.75 | 2.5 | 1.5 | 1.25 | 0.3 | 0.6 | 0.12 | 0.3 | 0.12 | 0.2 | 1.5
voile BA 20 cm | 002 R+1 | voile BA 20 cm | voile BA 20 cm 0.2 m | 1.45953 | 1.45953 | 1.45953 | 2.5 | 1.45953 | 1.45953 | 0.291906 | 0.583812 | 0.116762 | 0.291906 | 0.116762 | 0.2 | 1.45953
mur BBM 20 cm | 002 R+1 | mur BBM 20 cm | mur BBM 20 cm 0.2 m | 0.106433 | 0.106433 | 0.106433 | 2.5 | 0.106433 | 0.106433 | 0.0212866 | 0.0425733 | 0.00851465 | 0.0212866 | 0.00851465 | 0.2 | 0.106433
mur BBM 20 cm | 002 R+1 | mur BBM 20 cm | mur BBM 20 cm 0.2 m | 4.06523 | 3.49875 | 3.49875 | 2.5 | 3.78199 | 4.06523 | 0.756398 | 1.5128 | 0.302559 | 0.756398 | 0.302559 | 0.2 | 3.78199
mur BBM 20 cm | 002 R+1 | mur BBM 20 cm | mur BBM 20 cm 0.2 m | 8.35 | 8.35 | 8.35 | 2.5 | 8.35 | 8.35 | 1.67 | 3.34 | 0.668 | 1.67 | 0.668 | 0.2 | 8.35
mur BBM 20 cm | 002 R+1 | mur BBM 20 cm | mur BBM 20 cm 0.2 m | 4.75 | 4.75 | 2.6 | 2.5 | 2.6 | 2.6 | 0.52 | 1.9 | 0.38 | 0.95 | 0.38 | 0.2 | 4.75
4 x mur BBM 20 cm | 002 R+1 | mur BBM 20 cm | mur BBM 20 cm 0.2 m | 0.25 | 0.25 | 0.25 | 2.5 | 0.25 | 0.25 | 0.05 | 0.1 | 0.02 | 0.05 | 0.02 | 0.2 | 0.25
mur BBM 20 cm | 002 R+1 | mur BBM 20 cm | mur BBM 20 cm 0.2 m | 0.5 | 0.25 | 0.25 | 2.5 | 0.5 | 0.5 | 0.1 | 0.2 | 0.04 | 0.1 | 0.04 | 0.2 | 0.5
voile BA 20 cm | 002 R+1 | voile BA 20 cm | voile BA 20 cm 0.2 m | 3.75559 | 3.50559 | 3.50559 | 2.5 | 3.75559 | 3.75559 | 0.751119 | 1.50224 | 0.300448 | 0.751119 | 0.300448 | 0.2 | 3.75559
voile BA 20 cm | 002 R+1 | voile BA 20 cm | voile BA 20 cm 0.2 m | 0.75 | 1.25 | 1.25 | 2.5 | 1 | 0.75 | 0.2 | 0.4 | 0.08 | 0.2 | 0.08 | 0.2 | 1
mur BBM 20 cm | 002 R+1 | mur BBM 20 cm | mur BBM 20 cm 0.2 m | 0.0242369 | 0.0242369 | 0.0242369 | 2.5 | 0.0242369 | 0.0242369 | 0.00484738 | 0.00969476 | 0.00193895 | 0.00484738 | 0.00193895 | 0.2 | 0.0242369
voile BA 20 cm | 002 R+1 | voile BA 20 cm | voile BA 20 cm 0.2 m | 5.875 | 5.625 | 5.625 | 2.5 | 5.875 | 5.875 | 1.175 | 2.35 | 0.47 | 1.175 | 0.47 | 0.2 | 5.875
voile BA 20 cm | 002 R+1 | voile BA 20 cm | voile BA 20 cm 0.2 m | 2.625 | 2.625 | 0.475 | 2.5 | 0.475 | 0.475 | 0.095 | 1.05 | 0.01 | 0.525 | 0.21 | 0.2 | 2.625
mur BBM 15 cm allégés | 002 R+1 | mur BBM 15 cm allégés | mur BBM 15 cm allégés 0.15 m | 1.56011 | 1.39152 | 1.39152 | 1.05 | 1.47089 | 1.56011 | 0.220633 | 1.40084 | 0.210127 | 0.220633 | 0.210127 | 0.15 | 1.47089
mur BBM 15 cm allégés | 002 R+1 | mur BBM 15 cm allégés | mur BBM 15 cm allégés 0.15 m | 2.47235 | 2.6508 | 2.6508 | 1.05 | 2.56157 | 2.47235 | 0.384236 | 2.43959 | 0.365939 | 0.384236 | 0.365939 | 0.15 | 2.56157
mur BBM 15 cm allégés | 002 R+1 | mur BBM 15 cm allégés | mur BBM 15 cm allégés 0.15 m | 2.94 | 2.94 | 2.94 | 1.05 | 2.94 | 2.94 | 0.441 | 2.8 | 0.42 | 0.441 | 0.42 | 0.15 | 2.94
mur BBM 15 cm allégés | 002 R+1 | mur BBM 15 cm allégés | mur BBM 15 cm allégés 0.15 m | 2.28067 | 2.43777 | 2.43777 | 1.05 | 2.35922 | 2.28067 | 0.353883 | 2.24688 | 0.337031 | 0.353883 | 0.337031 | 0.15 | 2.35922
mur BBM 15 cm allégés | 002 R+1 | mur BBM 15 cm allégés | mur BBM 15 cm allégés 0.15 m | 2.95576 | 3.11306 | 3.11306 | 1.05 | 3.03451 | 2.95576 | 0.455176 | 2.89001 | 0.433501 | 0.455176 | 0.433501 | 0.15 | 3.03451
mur BBM 20 cm | 002 R+1 | mur BBM 20 cm | mur BBM 20 cm 0.2 m | 6.25 | 6.75 | 3.31546 | 2.5 | 3.06546 | 2.81546 | 0.613091 | 2.6 | 0.52 | 1.3 | 0.52 | 0.2 | 6.5
mur BBM 20 cm | 002 R+1 | mur BBM 20 cm | mur BBM 20 cm 0.2 m | 0.0312892 | 0.53519 | 0.53519 | 2.5 | 0.25195 | 0.0312892 | 0.0503901 | 0.10078 | 0.020156 | 0.0503901 | 0.020156 | 0.2 | 0.25195
mur BBM 20 cm | 002 R+1 | mur BBM 20 cm | mur BBM 20 cm 0.2 m | 11.6905 | 10.6827 | 10.6827 | 2.5 | 11.1866 | 11.6905 | 2.23732 | 4.47464 | 0.894928 | 2.23732 | 0.894928 | 0.2 | 11.1866
mur BBM 20 cm | 002 R+1 | mur BBM 20 cm | mur BBM 20 cm 0.2 m | 7.59993 | 7.10007 | 2.80007 | 2.5 | 3.05 | 3.29993 | 0.61 | 2.94 | 0.588 | 1.47 | 0.588 | 0.2 | 7.35
mur BBM 20 cm | 002 R+1 | mur BBM 20 cm | mur BBM 20 cm 0.2 m | 2.68326 | 2.68326 | 2.68326 | 0.94 | 2.68326 | 2.68326 | 0.536652 | 2.85453 | 0.570906 | 0.536652 | 0.570906 | 0.2 | 2.68326
voile BA 20 cm | 002 R+1 | voile BA 20 cm | voile BA 20 cm 0.2 m | 6.87456 | 7.12456 | 7.12456 | 2.5 | 7.12456 | 6.87456 | 1.42491 | 2.84982 | 0.569965 | 1.42491 | 0.569965 | 0.2 | 7.12456
voile BA 20 cm | 002 R+1 | voile BA 20 cm | voile BA 20 cm 0.2 m | 7.25 | 7.25 | 5.1 | 2.5 | 5.35 | 5.1 | 1.07 | 3 | 0.4 | 1.5 | 0.6 | 0.2 | 7.5
voile BA 20 cm | 002 R+1 | voile BA 20 cm | voile BA 20 cm 0.2 m | 1.75 | 1.25 | 1.25 | 2.5 | 1.5 | 1.75 | 0.3 | 0.6 | 0.12 | 0.3 | 0.12 | 0.2 | 1.5
voile BA 20 cm | 002 R+1 | voile BA 20 cm | voile BA 20 cm 0.2 m | 4.2 | 3.7 | 3.7 | 2.5 | 4.2 | 4.2 | 0.84 | 1.68 | 0.336 | 0.84 | 0.336 | 0.2 | 4.2
voile BA 20 cm | 002 R+1 | voile BA 20 cm | voile BA 20 cm 0.2 m | 2.225 | 2.725 | 2.725 | 2.5 | 2.475 | 2.225 | 0.495 | 0.99 | 0.198 | 0.495 | 0.198 | 0.2 | 2.475
mur BBM 20 cm | 002 R+1 | mur BBM 20 cm | mur BBM 20 cm 0.2 m | 3.23611 | 2.73626 | 1.41626 | 2.5 | 1.66619 | 1.91611 | 0.333238 | 1.19448 | 0.238895 | 0.597238 | 0.238895 | 0.2 | 2.98619
mur BBM 20 cm | 002 R+1 | mur BBM 20 cm | mur BBM 20 cm 0.2 m | 0.323419 | 0.323419 | 0.323419 | 2.5 | 0.323419 | 0.323419 | 0.0646838 | 0.129368 | 0.0258735 | 0.0646838 | 0.0258735 | 0.2 | 0.323419
mur BBM 20 cm | 002 R+1 | mur BBM 20 cm | mur BBM 20 cm 0.2 m | 7.16242 | 7.16242 | 7.16242 | 2.5 | 7.16242 | 7.16242 | 1.43248 | 2.86497 | 0.572993 | 1.43248 | 0.572993 | 0.2 | 7.16242
mur BBM 20 cm | 002 R+1 | mur BBM 20 cm | mur BBM 20 cm 0.2 m | 1.225 | 1.225 | 1.225 | 2.5 | 1.225 | 1.225 | 0.245 | 0.49 | 0.098 | 0.245 | 0.098 | 0.2 | 1.225
mur BBM 20 cm | 002 R+1 | mur BBM 20 cm | mur BBM 20 cm 0.2 m | 9.05678 | 9.18062 | 2.73062 | 2.5 | 2.85615 | 2.60678 | 0.57123 | 3.72246 | 0.744492 | 1.86123 | 0.744492 | 0.2 | 9.30615
voile BA 20 cm | 002 R+1 | voile BA 20 cm | voile BA 20 cm 0.2 m | 0.1875 | 0.1875 | 0.1875 | 2.5 | 0.1875 | 0.1875 | 0.0375 | 0.075 | 0.015 | 0.0375 | 0.015 | 0.2 | 0.1875
voile BA 20 cm | 002 R+1 | voile BA 20 cm | voile BA 20 cm 0.2 m | 0.975 | 1.475 | 1.475 | 2.5 | 1.225 | 0.975 | 0.245 | 0.49 | 0.098 | 0.245 | 0.098 | 0.2 | 1.225
mur BBM 20 cm | 002 R+1 | mur BBM 20 cm | mur BBM 20 cm 0.2 m | 8.85 | 8.85 | 8.85 | 2.5 | 8.85 | 8.85 | 1.77 | 3.54 | 0.708 | 1.77 | 0.708 | 0.2 | 8.85
mur BBM 20 cm | 002 R+1 | mur BBM 20 cm | mur BBM 20 cm 0.2 m | 10.7093 | 10.7093 | 10.7093 | 2.5 | 10.7093 | 10.7093 | 2.14185 | 4.28371 | 0.856742 | 2.14185 | 0.856742 | 0.2 | 10.7093
mur BBM 20 cm | 002 R+1 | mur BBM 20 cm | mur BBM 20 cm 0.2 m | 0.5 | 0.5 | 0.5 | 2.5 | 0.5 | 0.5 | 0.1 | 0.2 | 0.04 | 0.1 | 0.04 | 0.2 | 0.5
voile BA 20 cm | 002 R+1 | voile BA 20 cm | voile BA 20 cm 0.2 m | 0.5 | 0.5 | 0.5 | 2.5 | 0.5 | 0.5 | 0.1 | 0.2 | 0.04 | 0.1 | 0.04 | 0.2 | 0.5
voile BA 20 cm | 002 R+1 | voile BA 20 cm | voile BA 20 cm 0.2 m | 2.37544 | 1.87544 | 1.87544 | 2.5 | 2.12544 | 2.37544 | 0.425088 | 0.850177 | 0.170035 | 0.425088 | 0.170035 | 0.2 | 2.12544
mur BBM 20 cm | 002 R+1 | mur BBM 20 cm | mur BBM 20 cm 0.2 m | 0.000474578 | 0.000474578 | 0.000474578 | 2.5 | 0.000474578 | 0.000474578 | 0.0000949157 | 0.000189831 | 0.0000379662 | 0.0000949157 | 0.0000379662 | 0.2 | 0.000474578
voile BA 20 cm | 002 R+1 | voile BA 20 cm | voile BA 20 cm 0.2 m | 0.0625 | 0.4375 | 0.4375 | 2.5 | 0.1875 | 0.0625 | 0.0375 | 0.075 | 0.015 | 0.0375 | 0.015 | 0.2 | 0.1875
mur BBM 20 cm | 002 R+1 | mur BBM 20 cm | mur BBM 20 cm 0.2 m | 17.7369 | 18.2382 | 18.2382 | 2.5 | 17.9876 | 17.7369 | 3.59751 | 7.19502 | 1.439 | 3.59751 | 1.439 | 0.2 | 17.9876
mur BBM 20 cm | 002 R+1 | mur BBM 20 cm | mur BBM 20 cm 0.2 m | 16.1 | 15.85 | 12.88 | 2.5 | 13.13 | 13.13 | 2.626 | 6.44 | 1.288 | 3.22 | 1.288 | 0.2 | 16.1
voile BA 20 cm | 002 R+1 | voile BA 20 cm | voile BA 20 cm 0.2 m | 12.1001 | 12.1001 | 12.1001 | 2.5 | 12.1001 | 12.1001 | 2.42002 | 4.84004 | 0.968009 | 2.42002 | 0.968009 | 0.2 | 12.1001
voile BA 20 cm | 002 R+1 | voile BA 20 cm | voile BA 20 cm 0.2 m | 13 | 13 | 13 | 2.5 | 13 | 13 | 2.6 | 5.2 | 1.04 | 2.6 | 1.04 | 0.2 | 13
voile BA 20 cm | 002 R+1 | voile BA 20 cm | voile BA 20 cm 0.2 m | 0.399892 | 0.399892 | 0.399892 | 2.5 | 0.399892 | 0.399892 | 0.0799783 | 0.159957 | 0.0319913 | 0.0799783 | 0.0319913 | 0.2 | 0.399892
mur BBM 20 cm | 002 R+1 | mur BBM 20 cm | mur BBM 20 cm 0.2 m | 4.14357 | 3.89357 | 2.85857 | 2.5 | 3.10857 | 3.10857 | 0.621713 | 1.65743 | 0.331485 | 0.828713 | 0.331485 | 0.2 | 4.14357
voile BA 20 cm | 002 R+1 | voile BA 20 cm | voile BA 20 cm 0.2 m | 9.825 | 10.075 | 7.925 | 2.5 | 7.925 | 7.675 | 1.585 | 4.03 | 0.606 | 2.015 | 0.806 | 0.2 | 10.075
mur BBM 20 cm | 002 R+1 | mur BBM 20 cm | mur BBM 20 cm 0.2 m | 3.72775e-09 | 3.72775e-09 | 3.72775e-09 | 2.5 | 3.72775e-09 | 3.72775e-09 | 7.4555e-10 | 0.2 | 0.04 | 7.4555e-10 | 0.04 | 0.2 | 3.72775e-09
2 x PV BA 20 cm | 002 R+1 | PV BA 20 cm | PV BA 20 cm 0.2 m | 0.313 | 0.313 | 0.313 | 3.13 | 0.313 | 0.313 | 0.0626 | 0.1 | 0.02 | 0.0626 | 0.02 | 0.2 | 0.313
PV BA 20 cm | 002 R+1 | PV BA 20 cm | PV BA 20 cm 0.2 m | 10.7672 | 10.7672 | 9.2822 | 3.13 | 9.2822 | 9.2822 | 1.85644 | 3.44 | 0.688 | 2.15344 | 0.688 | 0.2 | 10.7672
PV BA 20 cm | 002 R+1 | PV BA 20 cm | PV BA 20 cm 0.2 m | 11.3932 | 11.3932 | 8.4232 | 3.13 | 8.4232 | 8.4232 | 1.68464 | 3.64 | 0.728 | 2.27864 | 0.728 | 0.2 | 11.3932
voile BA 20 cm | 002 R+1 | voile BA 20 cm | voile BA 20 cm 0.2 m | 0.3125 | 0.3125 | 0.3125 | 2.5 | 0.3125 | 0.3125 | 0.0625 | 0.125 | 0.025 | 0.0625 | 0.025 | 0.2 | 0.3125
mur BBM 15 cm | 003 R+2 | mur BBM 15 cm | mur BBM 15 cm 0.15 m | 1.8225 | 2.025 | 2.025 | 1.35 | 1.92375 | 1.8225 | 0.288563 | 1.425 | 0.21375 | 0.288563 | 0.21375 | 0.15 | 1.92375
mur BBM 15 cm | 003 R+2 | mur BBM 15 cm | mur BBM 15 cm 0.15 m | 9.612 | 9.8145 | 9.8145 | 1.35 | 9.71325 | 9.612 | 1.45699 | 7.195 | 1.07925 | 1.45699 | 1.07925 | 0.15 | 9.71325
mur BBM 15 cm | 003 R+2 | mur BBM 15 cm | mur BBM 15 cm 0.15 m | 2.09257 | 2.26755 | 2.26755 | 1.35 | 2.16656 | 2.09257 | 0.324984 | 1.60486 | 0.240729 | 0.324984 | 0.240729 | 0.15 | 2.16656
mur BBM 15 cm | 003 R+2 | mur BBM 15 cm | mur BBM 15 cm 0.15 m | 4.93105 | 5.13303 | 5.13303 | 1.35 | 5.03204 | 4.93105 | 0.754806 | 3.72744 | 0.559116 | 0.754806 | 0.559116 | 0.15 | 5.03204
mur BBM 15 cm | 003 R+2 | mur BBM 15 cm | mur BBM 15 cm 0.15 m | 6.4564 | 6.68583 | 6.68583 | 1.35 | 6.57111 | 6.4564 | 0.985667 | 4.86749 | 0.730124 | 0.985667 | 0.730124 | 0.15 | 6.57111
mur BBM 15 cm | 003 R+2 | mur BBM 15 cm | mur BBM 15 cm 0.15 m | 2.01359 | 1.83644 | 1.83644 | 1.35 | 1.89888 | 2.01359 | 0.284831 | 1.40657 | 0.210986 | 0.284831 | 0.210986 | 0.15 | 1.89888
mur BBM 20 cm | 003 R+2 | mur BBM 20 cm | mur BBM 20 cm 0.2 m | 0.0755851 | 0.145076 | 0.145076 | 2.5 | 0.0755851 | 0.0755851 | 0.015117 | 0.030234 | 0.00604681 | 0.015117 | 0.00604681 | 0.2 | 0.0755851
mur BBM 20 cm | 003 R+2 | mur BBM 20 cm | mur BBM 20 cm 0.2 m | 6.85 | 7.35 | 3.05 | 2.5 | 3.05 | 2.55 | 0.61 | 2.94 | 0.588 | 1.47 | 0.588 | 0.2 | 7.35
mur BBM 20 cm | 003 R+2 | mur BBM 20 cm | mur BBM 20 cm 0.2 m | 0.207654 | 0.0755851 | 0.0755851 | 2.5 | 0.0755851 | 0.207654 | 0.015117 | 0.030234 | 0.00604681 | 0.015117 | 0.00604681 | 0.2 | 0.0755851
mur BBM 20 cm | 003 R+2 | mur BBM 20 cm | mur BBM 20 cm 0.2 m | 11.6905 | 10.6827 | 10.6827 | 2.5 | 11.1866 | 11.6905 | 2.23732 | 4.47464 | 0.894928 | 2.23732 | 0.894928 | 0.2 | 11.1866
mur BBM 20 cm | 003 R+2 | mur BBM 20 cm | mur BBM 20 cm 0.2 m | 11.5453 | 11.104 | 8.13399 | 2.5 | 8.35465 | 8.57531 | 1.67093 | 4.52986 | 0.905972 | 2.26493 | 0.905972 | 0.2 | 11.3247
mur BBM 20 cm | 003 R+2 | mur BBM 20 cm | mur BBM 20 cm 0.2 m | 24.65 | 25.65 | 25.65 | 2.5 | 25.15 | 24.65 | 5.02999 | 10.06 | 2.012 | 5.02999 | 2.012 | 0.2 | 25.15
mur BBM 20 cm | 003 R+2 | mur BBM 20 cm | mur BBM 20 cm 0.2 m | 9.31779 | 9.44152 | 5.44152 | 2.5 | 5.56716 | 5.31779 | 1.11343 | 3.82686 | 0.765373 | 1.91343 | 0.765373 | 0.2 | 9.56716
voile BA 20 cm | 003 R+2 | voile BA 20 cm | voile BA 20 cm 0.2 m | 11.3 | 11.8 | 11.8 | 2.5 | 11.55 | 11.3 | 2.31 | 4.62 | 0.924 | 2.31 | 0.924 | 0.2 | 11.55
voile BA 20 cm | 003 R+2 | voile BA 20 cm | voile BA 20 cm 0.2 m | 0.4 | 0.9 | 0.9 | 2.5 | 0.65 | 0.4 | 0.13 | 0.26 | 0.052 | 0.13 | 0.052 | 0.2 | 0.65
voile BA 20 cm | 003 R+2 | voile BA 20 cm | voile BA 20 cm 0.2 m | 0.469977 | 0.0300232 | 0.0300232 | 2.5 | 0.219977 | 0.469977 | 0.0439954 | 0.0879907 | 0.0175981 | 0.0439954 | 0.0175981 | 0.2 | 0.219977
voile BA 20 cm | 003 R+2 | voile BA 20 cm | voile BA 20 cm 0.2 m | 13.75 | 14.25 | 14.25 | 2.5 | 14 | 13.75 | 2.8 | 5.6 | 1.12 | 2.8 | 1.12 | 0.2 | 14
mur BBM 20 cm | 003 R+2 | mur BBM 20 cm | mur BBM 20 cm 0.2 m | 7.5 | 7 | 5.965 | 2.5 | 6.465 | 6.465 | 1.293 | 3 | 0.6 | 1.5 | 0.6 | 0.2 | 7.5
voile BA 20 cm | 003 R+2 | voile BA 20 cm | voile BA 20 cm 0.2 m | 4.94989 | 5.44989 | 3.29989 | 2.5 | 3.04989 | 2.79989 | 0.609978 | 2.07996 | 0.215991 | 1.03998 | 0.415991 | 0.2 | 5.19989
voile BA 20 cm | 003 R+2 | voile BA 20 cm | voile BA 20 cm 0.2 m | 12.3501 | 12.3501 | 10.2001 | 2.5 | 10.2001 | 10.2001 | 2.04002 | 4.94004 | 0.788009 | 2.47002 | 0.988009 | 0.2 | 12.3501
mur BBM 20 cm | 003 R+2 | mur BBM 20 cm | mur BBM 20 cm 0.2 m | 12.3822 | 12.1322 | 9.16224 | 2.5 | 9.41224 | 9.41224 | 1.88245 | 4.9529 | 0.990579 | 2.47645 | 0.990579 | 0.2 | 12.3822
voile BA 20 cm | 003 R+2 | voile BA 20 cm | voile BA 20 cm 0.2 m | 5.625 | 5.875 | 5.875 | 2.5 | 5.875 | 5.625 | 1.175 | 2.35 | 0.47 | 1.175 | 0.47 | 0.2 | 5.875
voile BA 20 cm | 003 R+2 | voile BA 20 cm | voile BA 20 cm 0.2 m | 3.55 | 3.05 | 0.9 | 2.5 | 1.15 | 1.4 | 0.23 | 1.32 | 0.064 | 0.66 | 0.264 | 0.2 | 3.3
voile BA 20 cm | 003 R+2 | voile BA 20 cm | voile BA 20 cm 0.2 m | 9.825 | 10.075 | 7.925 | 2.5 | 7.925 | 7.675 | 1.585 | 4.03 | 0.606 | 2.015 | 0.806 | 0.2 | 10.075
voile BA 20 cm | 003 R+2 | voile BA 20 cm | voile BA 20 cm 0.2 m | 1.25 | 1.75 | 1.75 | 2.5 | 1.5 | 1.25 | 0.3 | 0.6 | 0.12 | 0.3 | 0.12 | 0.2 | 1.5
voile BA 20 cm | 003 R+2 | voile BA 20 cm | voile BA 20 cm 0.2 m | 5.50161 | 5.25161 | 5.25161 | 2.5 | 5.50161 | 5.50161 | 1.10032 | 2.20064 | 0.440129 | 1.10032 | 0.440129 | 0.2 | 5.50161
voile BA 20 cm | 003 R+2 | voile BA 20 cm | voile BA 20 cm 0.2 m | 2.475 | 2.975 | 2.975 | 2.5 | 2.725 | 2.475 | 0.545 | 1.09 | 0.218 | 0.545 | 0.218 | 0.2 | 2.725
voile BA 20 cm | 003 R+2 | voile BA 20 cm | voile BA 20 cm 0.2 m | 1.225 | 1.725 | 1.725 | 2.5 | 1.475 | 1.225 | 0.295 | 0.59 | 0.118 | 0.295 | 0.118 | 0.2 | 1.475
voile BA 20 cm | 003 R+2 | voile BA 20 cm | voile BA 20 cm 0.2 m | 1.75 | 1.25 | 1.25 | 2.5 | 1.5 | 1.75 | 0.3 | 0.6 | 0.12 | 0.3 | 0.12 | 0.2 | 1.5
voile BA 20 cm | 003 R+2 | voile BA 20 cm | voile BA 20 cm 0.2 m | 4.2 | 3.7 | 3.7 | 2.5 | 4.2 | 4.2 | 0.84 | 1.68 | 0.336 | 0.84 | 0.336 | 0.2 | 4.2
mur BBM 20 cm | 003 R+2 | mur BBM 20 cm | mur BBM 20 cm 0.2 m | 11.3954 | 11.584 | 5.58398 | 2.5 | 5.67866 | 5.39541 | 1.13573 | 4.67146 | 0.934293 | 2.33573 | 0.934293 | 0.2 | 11.6787
mur BBM 20 cm | 003 R+2 | mur BBM 20 cm | mur BBM 20 cm 0.2 m | 11.5399 | 10.532 | 9.04704 | 2.5 | 9.55095 | 10.0549 | 1.91019 | 4.41438 | 0.882876 | 2.20719 | 0.882876 | 0.2 | 11.036
mur BBM 20 cm | 003 R+2 | mur BBM 20 cm | mur BBM 20 cm 0.2 m | 6.97661 | 6.97661 | 4.97661 | 2.5 | 4.97661 | 4.97661 | 0.995322 | 2.79064 | 0.558129 | 1.39532 | 0.558129 | 0.2 | 6.97661
mur BBM 20 cm | 003 R+2 | mur BBM 20 cm | mur BBM 20 cm 0.2 m | 3.07022 | 2.88272 | 2.88272 | 2.5 | 3.07022 | 3.07022 | 0.614044 | 1.22809 | 0.245618 | 0.614044 | 0.245618 | 0.2 | 3.07022
mur BBM 20 cm | 003 R+2 | mur BBM 20 cm | mur BBM 20 cm 0.2 m | 9.88206 | 9.38079 | 7.89579 | 2.5 | 8.14642 | 8.39706 | 1.62928 | 3.85257 | 0.770514 | 1.92628 | 0.770514 | 0.2 | 9.63142
mur BBM 20 cm | 003 R+2 | mur BBM 20 cm | mur BBM 20 cm 0.2 m | 16.0993 | 15.8493 | 12.8793 | 2.5 | 13.1293 | 13.1293 | 2.62586 | 6.43973 | 1.28795 | 3.21986 | 1.28795 | 0.2 | 16.0993
voile BA 20 cm | 003 R+2 | voile BA 20 cm | voile BA 20 cm 0.2 m | 3.48002 | 3.23002 | 3.23002 | 2.5 | 3.48002 | 3.48002 | 0.696005 | 1.39201 | 0.278402 | 0.696005 | 0.278402 | 0.2 | 3.48002
voile BA 20 cm | 003 R+2 | voile BA 20 cm | voile BA 20 cm 0.2 m | 3.8 | 3.3 | 3.3 | 2.5 | 3.55 | 3.8 | 0.71 | 1.42 | 0.284 | 0.71 | 0.284 | 0.2 | 3.55
voile BA 20 cm | 003 R+2 | voile BA 20 cm | voile BA 20 cm 0.2 m | 1.74839 | 2.24839 | 2.24839 | 2.5 | 1.99839 | 1.74839 | 0.399678 | 0.799355 | 0.159871 | 0.399678 | 0.159871 | 0.2 | 1.99839
mur BBM 20 cm | 003 R+2 | mur BBM 20 cm | mur BBM 20 cm 0.2 m | 11.3109 | 11.1234 | 5.63839 | 2.5 | 5.82589 | 5.82589 | 1.16518 | 4.52436 | 0.904871 | 2.26218 | 0.904871 | 0.2 | 11.3109
mur BBM 20 cm | 003 R+2 | mur BBM 20 cm | mur BBM 20 cm 0.2 m | 3.54929 | 4.33253 | 4.33253 | 2.5 | 4.08253 | 3.54929 | 0.816506 | 1.63301 | 0.326602 | 0.816506 | 0.326602 | 0.2 | 4.08253
mur BBM 20 cm | 003 R+2 | mur BBM 20 cm | mur BBM 20 cm 0.2 m | 3.41263 | 2.69197 | 1.37197 | 2.5 | 1.84263 | 2.09263 | 0.368526 | 1.26505 | 0.25301 | 0.632526 | 0.25301 | 0.2 | 3.16263
mur BBM 20 cm | 003 R+2 | mur BBM 20 cm | mur BBM 20 cm 0.2 m | 2.07103 | 2.07103 | 2.07103 | 0.75 | 2.07103 | 2.07103 | 0.414206 | 2.76138 | 0.552275 | 0.414206 | 0.552275 | 0.2 | 2.07103
2 x PV BA 20 cm | 003 R+2 | PV BA 20 cm | PV BA 20 cm 0.2 m | 0.27 | 0.27 | 0.27 | 2.7 | 0.27 | 0.27 | 0.054 | 0.1 | 0.02 | 0.054 | 0.02 | 0.2 | 0.27
PV BA 20 cm | 003 R+2 | PV BA 20 cm | PV BA 20 cm 0.2 m | 19.116 | 19.116 | 14.661 | 2.7 | 14.661 | 14.661 | 2.9322 | 7.08 | 1.416 | 3.8232 | 1.416 | 0.2 | 19.116
acrotère Blocs à bancher 20 cm | 004 Toiture Terrasse | acrotère Blocs à bancher 20 cm | acrotère Blocs à bancher 20 cm 0.2 m | 28.7045 | 28.2332 | 28.2332 | 1.25 | 28.4688 | 28.7045 | 5.69376 | 22.7751 | 4.55501 | 5.69376 | 4.55501 | 0.2 | 28.4688
acrotère Blocs à bancher 20 cm | 004 Toiture Terrasse | acrotère Blocs à bancher 20 cm | acrotère Blocs à bancher 20 cm 0.2 m | 12.325 | 12.825 | 12.825 | 1.25 | 12.575 | 12.325 | 2.515 | 10.06 | 2.012 | 2.515 | 2.012 | 0.2 | 12.575
acrotère Blocs à bancher 20 cm | 004 Toiture Terrasse | acrotère Blocs à bancher 20 cm | acrotère Blocs à bancher 20 cm 0.2 m | 4.78384 | 4.7832 | 4.7832 | 1.25 | 4.78352 | 4.78384 | 0.956704 | 3.82681 | 0.765363 | 0.956704 | 0.765363 | 0.2 | 4.78352
acrotère Blocs à bancher 20 cm | 004 Toiture Terrasse | acrotère Blocs à bancher 20 cm | acrotère Blocs à bancher 20 cm 0.2 m | 2.12505 | 2.12505 | 2.12505 | 1.25 | 2.12505 | 2.12505 | 0.425011 | 1.70004 | 0.340009 | 0.425011 | 0.340009 | 0.2 | 2.12505
acrotère Blocs à bancher 20 cm | 004 Toiture Terrasse | acrotère Blocs à bancher 20 cm | acrotère Blocs à bancher 20 cm 0.2 m | 10.6789 | 10.6789 | 10.6789 | 1.25 | 10.6789 | 10.6789 | 2.13577 | 8.54309 | 1.70862 | 2.13577 | 1.70862 | 0.2 | 10.6789
2 x acrotère Blocs à bancher 20 cm | 004 Toiture Terrasse | acrotère Blocs à bancher 20 cm | acrotère Blocs à bancher 20 cm 0.2 m | 3.70625 | 3.70625 | 3.70625 | 1.25 | 3.70625 | 3.70625 | 0.74125 | 2.965 | 0.593 | 0.74125 | 0.593 | 0.2 | 3.70625
acrotère Blocs à bancher 20 cm | 004 Toiture Terrasse | acrotère Blocs à bancher 20 cm | acrotère Blocs à bancher 20 cm 0.2 m | 8.6 | 9.1 | 9.1 | 1.25 | 8.85 | 8.6 | 1.77 | 7.08 | 1.416 | 1.77 | 1.416 | 0.2 | 8.85
acrotère Blocs à bancher 20 cm | 004 Toiture Terrasse | acrotère Blocs à bancher 20 cm | acrotère Blocs à bancher 20 cm 0.2 m | 5.94767 | 5.98091 | 5.98091 | 1.25 | 5.96429 | 5.94767 | 1.19286 | 4.77143 | 0.954287 | 1.19286 | 0.954287 | 0.2 | 5.96429
acrotère Blocs à bancher 20 cm | 004 Toiture Terrasse | acrotère Blocs à bancher 20 cm | acrotère Blocs à bancher 20 cm 0.2 m | 15.0666 | 14.5627 | 14.5627 | 1.25 | 14.8147 | 15.0666 | 2.96294 | 11.8517 | 2.37035 | 2.96294 | 2.37035 | 0.2 | 14.8147

# IfcWindow (48)
Description: Fenêtre
Name | In | OverallHeight (m) | OverallWidth (m)
5 x BL 300 x 115 | 001 RdC | 1.15 | 3
BL 200 x 115 | 001 RdC | 1.15 | 2
4 x BL 90 x 115 | 001 RdC | 1.15 | 0.9
BL 90 x 195 | 001 RdC | 1.95 | 0.9
BL 300 x 215 | 001 RdC | 2.15 | 3
10 x BL 90 x 165 | 002 R+1 | 1.65 | 0.9
3 x BL 300 x 215 | 002 R+1 | 2.15 | 3
BL 80 x 165 | 002 R+1 | 1.65 | 0.8
BL 200 x 215 | 002 R+1 | 2.15 | 2
BL 90 x 115 | 002 R+1 | 1.15 | 0.9
BL 100 x 215 | 002 R+1 | 2.15 | 1
12 x BL 90 x 165 | 003 R+2 | 1.65 | 0.9
BL 300 x 215 | 003 R+2 | 2 | 3
2 x BL 200 x 200 | 003 R+2 | 2 | 2
BL 100 x 200 | 003 R+2 | 2 | 1
BL 80 x 165 | 003 R+2 | 1.65 | 0.8
BL 200 x 215 | 003 R+2 | 2.15 | 2
BL 90 x 115 | 003 R+2 | 1.15 | 0.9
